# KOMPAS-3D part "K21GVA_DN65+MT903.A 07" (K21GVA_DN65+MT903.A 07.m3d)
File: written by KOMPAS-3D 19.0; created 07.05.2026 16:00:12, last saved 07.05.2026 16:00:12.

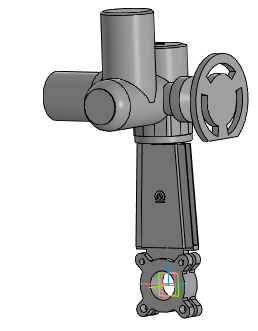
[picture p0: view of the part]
Document properties: Автор: Энергия; Полное имя файла: ..\K21GVA_DN50-DN1000+MT903.A\K21GVA_DN65+MT903.A 07.a3d

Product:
- Part/product: K21GVA_DN65+MT903.A 07
    Масса: 73.3661

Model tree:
1. Операция без истории:1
